One B-rep face of a CAD part: STEP entity #532.
In plain terms, the planar face has unit normal (1, 0, 0).
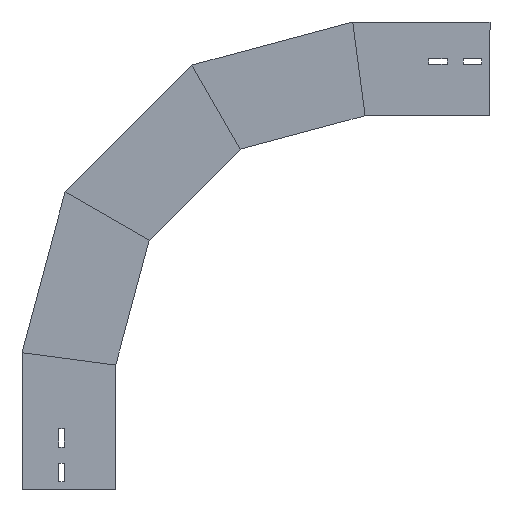
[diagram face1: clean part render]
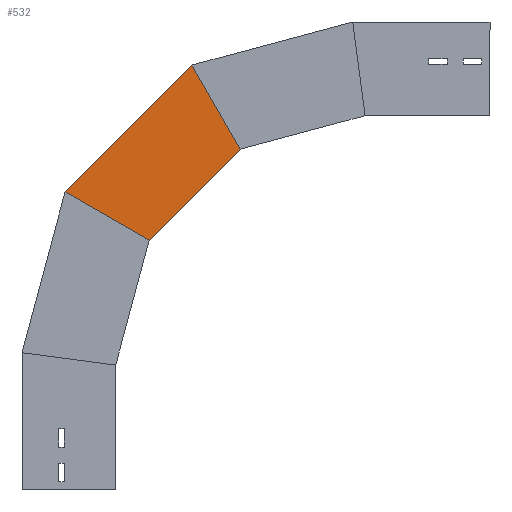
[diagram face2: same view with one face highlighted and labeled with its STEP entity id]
Its self-contained STEP definition (entity closure, numbers rounded to 3 decimals):
#10 = VECTOR ( 'NONE', #1345, 1000. ) ;
#67 = CARTESIAN_POINT ( 'NONE',  ( 0., -78.533, 277.539 ) ) ;
#96 = DIRECTION ( 'NONE',  ( 1., 0., 0. ) ) ;
#229 = LINE ( 'NONE', #67, #1814 ) ;
#277 = VERTEX_POINT ( 'NONE', #744 ) ;
#333 = CARTESIAN_POINT ( 'NONE',  ( 0., -174.081, 367.123 ) ) ;
#381 = VERTEX_POINT ( 'NONE', #1529 ) ;
#460 = ORIENTED_EDGE ( 'NONE', *, *, #1880, .T. ) ;
#465 = DIRECTION ( 'NONE',  ( 0., -0.5, -0.866 ) ) ;
#524 = CARTESIAN_POINT ( 'NONE',  ( 0., -16.599, 276.201 ) ) ;
#532 = ADVANCED_FACE ( 'NONE', ( #533 ), #1705, .T. ) ;
#533 = FACE_OUTER_BOUND ( 'NONE', #875, .T. ) ;
#541 = DIRECTION ( 'NONE',  ( 0., -0.866, -0.5 ) ) ;
#601 = CARTESIAN_POINT ( 'NONE',  ( 0., 62.95, 355.751 ) ) ;
#743 = ORIENTED_EDGE ( 'NONE', *, *, #1116, .T. ) ;
#744 = CARTESIAN_POINT ( 'NONE',  ( 0., -149.719, 409.32 ) ) ;
#875 = EDGE_LOOP ( 'NONE', ( #460, #743, #1372, #1050 ) ) ;
#927 = VECTOR ( 'NONE', #465, 1000. ) ;
#948 = EDGE_CURVE ( 'NONE', #1843, #1261, #229, .T. ) ;
#1050 = ORIENTED_EDGE ( 'NONE', *, *, #948, .F. ) ;
#1071 = DIRECTION ( 'NONE',  ( 0., -0.707, 0.707 ) ) ;
#1105 = EDGE_CURVE ( 'NONE', #1261, #277, #1773, .T. ) ;
#1116 = EDGE_CURVE ( 'NONE', #381, #277, #1629, .T. ) ;
#1118 = CARTESIAN_POINT ( 'NONE',  ( 0., -40.117, 299.719 ) ) ;
#1235 = VECTOR ( 'NONE', #1071, 1000. ) ;
#1247 = DIRECTION ( 'NONE',  ( 0., 0., -1. ) ) ;
#1261 = VERTEX_POINT ( 'NONE', #1118 ) ;
#1345 = DIRECTION ( 'NONE',  ( 0., -0.707, 0.707 ) ) ;
#1372 = ORIENTED_EDGE ( 'NONE', *, *, #1105, .F. ) ;
#1529 = CARTESIAN_POINT ( 'NONE',  ( 0., -91.484, 510.185 ) ) ;
#1560 = LINE ( 'NONE', #601, #10 ) ;
#1621 = CARTESIAN_POINT ( 'NONE',  ( 0., 60.748, 357.953 ) ) ;
#1629 = LINE ( 'NONE', #333, #927 ) ;
#1705 = PLANE ( 'NONE',  #1752 ) ;
#1752 = AXIS2_PLACEMENT_3D ( 'NONE', #524, #96, #1247 ) ;
#1773 = LINE ( 'NONE', #1795, #1235 ) ;
#1795 = CARTESIAN_POINT ( 'NONE',  ( 0., -16.599, 276.201 ) ) ;
#1814 = VECTOR ( 'NONE', #541, 1000. ) ;
#1843 = VERTEX_POINT ( 'NONE', #1621 ) ;
#1880 = EDGE_CURVE ( 'NONE', #1843, #381, #1560, .T. ) ;
